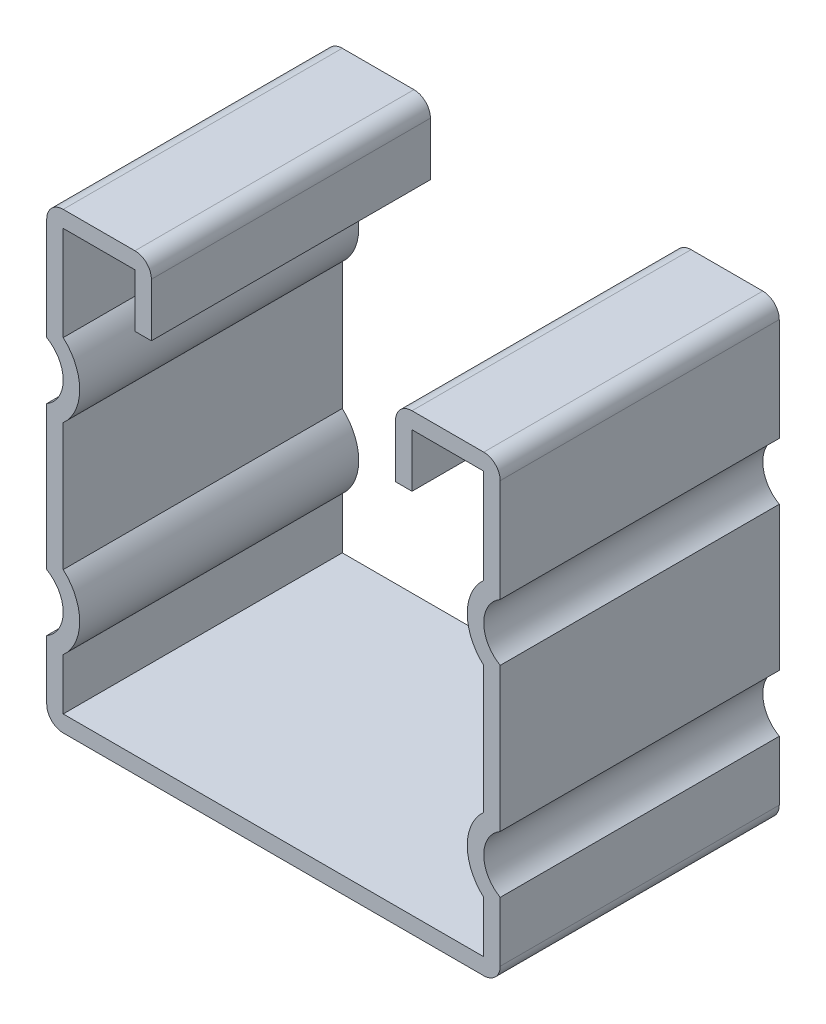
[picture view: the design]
ISO-10303-21;
HEADER;
FILE_DESCRIPTION(('STEP AP214'),'2;1');
FILE_NAME('part.step','',(''),(''),'','','');
FILE_SCHEMA(('AUTOMOTIVE_DESIGN { 1 0 10303 214 1 1 1 1 }'));
ENDSEC;
DATA;
#1=APPLICATION_CONTEXT('core data for automotive mechanical design processes');
#2=APPLICATION_PROTOCOL_DEFINITION('international standard','automotive_design',2000,#1);
#3=PRODUCT_CONTEXT('',#1,'mechanical');
#4=PRODUCT('Part','Part','',(#3));
#5=PRODUCT_RELATED_PRODUCT_CATEGORY('part','',(#4));
#6=PRODUCT_DEFINITION_FORMATION('','',#4);
#7=PRODUCT_DEFINITION_CONTEXT('part definition',#1,'design');
#8=PRODUCT_DEFINITION('design','',#6,#7);
#9=PRODUCT_DEFINITION_SHAPE('','',#8);
#10=(LENGTH_UNIT() NAMED_UNIT(*) SI_UNIT(.MILLI.,.METRE.));
#11=(NAMED_UNIT(*) PLANE_ANGLE_UNIT() SI_UNIT($,.RADIAN.));
#12=(NAMED_UNIT(*) SI_UNIT($,.STERADIAN.) SOLID_ANGLE_UNIT());
#13=UNCERTAINTY_MEASURE_WITH_UNIT(LENGTH_MEASURE(1.E-05),#10,'distance_accuracy_value','');
#14=(GEOMETRIC_REPRESENTATION_CONTEXT(3) GLOBAL_UNCERTAINTY_ASSIGNED_CONTEXT((#13)) GLOBAL_UNIT_ASSIGNED_CONTEXT((#10,
#11,#12)) REPRESENTATION_CONTEXT('',''));
#15=CARTESIAN_POINT('',(0.,0.,0.));
#16=DIRECTION('',(0.,0.,1.));
#17=DIRECTION('',(1.,0.,0.));
#18=AXIS2_PLACEMENT_3D('',#15,#16,#17);
#19=CARTESIAN_POINT('',(-19.1389,21.1074,12.7));
#20=DIRECTION('',(-1.,0.,0.));
#21=DIRECTION('',(0.,-1.,0.));
#22=AXIS2_PLACEMENT_3D('',#19,#20,#21);
#23=PLANE('',#22);
#24=DIRECTION('',(0.,1.,0.));
#25=VECTOR('',#24,1.);
#26=CARTESIAN_POINT('',(-19.1389,21.1074,-12.7));
#27=LINE('',#26,#25);
#28=CARTESIAN_POINT('',(-19.1389,12.4949714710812,-12.7));
#29=VERTEX_POINT('',#28);
#30=CARTESIAN_POINT('',(-19.1389,21.1074,-12.7));
#31=VERTEX_POINT('',#30);
#32=EDGE_CURVE('E323',#29,#31,#27,.T.);
#33=ORIENTED_EDGE('',*,*,#32,.T.);
#34=DIRECTION('',(0.,0.,-1.));
#35=VECTOR('',#34,1.);
#36=CARTESIAN_POINT('',(-19.1389,21.1074,12.7));
#37=LINE('',#36,#35);
#38=CARTESIAN_POINT('',(-19.1389,21.1074,12.7));
#39=VERTEX_POINT('',#38);
#40=EDGE_CURVE('E11',#39,#31,#37,.T.);
#41=ORIENTED_EDGE('',*,*,#40,.F.);
#42=DIRECTION('',(0.,1.,0.));
#43=VECTOR('',#42,1.);
#44=CARTESIAN_POINT('',(-19.1389,21.1074,12.7));
#45=LINE('',#44,#43);
#46=CARTESIAN_POINT('',(-19.1389,12.4949714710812,12.7));
#47=VERTEX_POINT('',#46);
#48=EDGE_CURVE('E436',#47,#39,#45,.T.);
#49=ORIENTED_EDGE('',*,*,#48,.F.);
#50=DIRECTION('',(0.,0.,-1.));
#51=VECTOR('',#50,1.);
#52=CARTESIAN_POINT('',(-19.1389,12.4949714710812,12.7));
#53=LINE('',#52,#51);
#54=EDGE_CURVE('E322',#47,#29,#53,.T.);
#55=ORIENTED_EDGE('',*,*,#54,.T.);
#56=EDGE_LOOP('',(#33,#41,#49,#55));
#57=FACE_BOUND('',#56,.T.);
#58=ADVANCED_FACE('F41',(#57),#23,.F.);
#59=CARTESIAN_POINT('',(-19.1389,21.1074,12.7));
#60=DIRECTION('',(0.,1.,0.));
#61=DIRECTION('',(-1.,0.,0.));
#62=AXIS2_PLACEMENT_3D('',#59,#60,#61);
#63=PLANE('',#62);
#64=DIRECTION('',(1.,0.,0.));
#65=VECTOR('',#64,1.);
#66=CARTESIAN_POINT('',(-19.1389,21.1074,-12.7));
#67=LINE('',#66,#65);
#68=CARTESIAN_POINT('',(-12.6111,21.1074,-12.7));
#69=VERTEX_POINT('',#68);
#70=EDGE_CURVE('E330',#31,#69,#67,.T.);
#71=ORIENTED_EDGE('',*,*,#70,.T.);
#72=DIRECTION('',(0.,0.,-1.));
#73=VECTOR('',#72,1.);
#74=CARTESIAN_POINT('',(-12.6111,21.1074,12.7));
#75=LINE('',#74,#73);
#76=CARTESIAN_POINT('',(-12.6111,21.1074,12.7));
#77=VERTEX_POINT('',#76);
#78=EDGE_CURVE('E49',#77,#69,#75,.T.);
#79=ORIENTED_EDGE('',*,*,#78,.F.);
#80=DIRECTION('',(1.,0.,0.));
#81=VECTOR('',#80,1.);
#82=CARTESIAN_POINT('',(-19.1389,21.1074,12.7));
#83=LINE('',#82,#81);
#84=EDGE_CURVE('E192',#39,#77,#83,.T.);
#85=ORIENTED_EDGE('',*,*,#84,.F.);
#86=ORIENTED_EDGE('',*,*,#40,.T.);
#87=EDGE_LOOP('',(#71,#79,#85,#86));
#88=FACE_BOUND('',#87,.T.);
#89=ADVANCED_FACE('F806',(#88),#63,.F.);
#90=CARTESIAN_POINT('',(-12.6111,21.1074,12.7));
#91=DIRECTION('',(1.,0.,0.));
#92=DIRECTION('',(0.,0.,-1.));
#93=AXIS2_PLACEMENT_3D('',#90,#91,#92);
#94=PLANE('',#93);
#95=DIRECTION('',(0.,-1.,0.));
#96=VECTOR('',#95,1.);
#97=CARTESIAN_POINT('',(-12.6111,21.1074,-12.7));
#98=LINE('',#97,#96);
#99=CARTESIAN_POINT('',(-12.6111,16.256,-12.7));
#100=VERTEX_POINT('',#99);
#101=EDGE_CURVE('E334',#69,#100,#98,.T.);
#102=ORIENTED_EDGE('',*,*,#101,.T.);
#103=DIRECTION('',(0.,0.,-1.));
#104=VECTOR('',#103,1.);
#105=CARTESIAN_POINT('',(-12.6111,16.256,12.7));
#106=LINE('',#105,#104);
#107=CARTESIAN_POINT('',(-12.6111,16.256,12.7));
#108=VERTEX_POINT('',#107);
#109=EDGE_CURVE('E566',#108,#100,#106,.T.);
#110=ORIENTED_EDGE('',*,*,#109,.F.);
#111=DIRECTION('',(0.,-1.,0.));
#112=VECTOR('',#111,1.);
#113=CARTESIAN_POINT('',(-12.6111,21.1074,12.7));
#114=LINE('',#113,#112);
#115=EDGE_CURVE('E579',#77,#108,#114,.T.);
#116=ORIENTED_EDGE('',*,*,#115,.F.);
#117=ORIENTED_EDGE('',*,*,#78,.T.);
#118=EDGE_LOOP('',(#102,#110,#116,#117));
#119=FACE_BOUND('',#118,.T.);
#120=ADVANCED_FACE('F577',(#119),#94,.F.);
#121=CARTESIAN_POINT('',(-12.6111,16.256,12.7));
#122=DIRECTION('',(0.,1.,0.));
#123=DIRECTION('',(0.,0.,1.));
#124=AXIS2_PLACEMENT_3D('',#121,#122,#123);
#125=PLANE('',#124);
#126=DIRECTION('',(1.,0.,0.));
#127=VECTOR('',#126,1.);
#128=CARTESIAN_POINT('',(-12.6111,16.256,-12.7));
#129=LINE('',#128,#127);
#130=CARTESIAN_POINT('',(-11.1125,16.256,-12.7));
#131=VERTEX_POINT('',#130);
#132=EDGE_CURVE('E333',#100,#131,#129,.T.);
#133=ORIENTED_EDGE('',*,*,#132,.T.);
#134=DIRECTION('',(0.,0.,-1.));
#135=VECTOR('',#134,1.);
#136=CARTESIAN_POINT('',(-11.1125,16.256,12.7));
#137=LINE('',#136,#135);
#138=CARTESIAN_POINT('',(-11.1125,16.256,12.7));
#139=VERTEX_POINT('',#138);
#140=EDGE_CURVE('E565',#139,#131,#137,.T.);
#141=ORIENTED_EDGE('',*,*,#140,.F.);
#142=DIRECTION('',(1.,0.,0.));
#143=VECTOR('',#142,1.);
#144=CARTESIAN_POINT('',(-12.6111,16.256,12.7));
#145=LINE('',#144,#143);
#146=EDGE_CURVE('E600',#108,#139,#145,.T.);
#147=ORIENTED_EDGE('',*,*,#146,.F.);
#148=ORIENTED_EDGE('',*,*,#109,.T.);
#149=EDGE_LOOP('',(#133,#141,#147,#148));
#150=FACE_BOUND('',#149,.T.);
#151=ADVANCED_FACE('F589',(#150),#125,.F.);
#152=CARTESIAN_POINT('',(-11.1125,21.1074,12.7));
#153=DIRECTION('',(-1.,0.,0.));
#154=DIRECTION('',(0.,-1.,0.));
#155=AXIS2_PLACEMENT_3D('',#152,#153,#154);
#156=PLANE('',#155);
#157=DIRECTION('',(0.,1.,0.));
#158=VECTOR('',#157,1.);
#159=CARTESIAN_POINT('',(-11.1125,21.1074,-12.7));
#160=LINE('',#159,#158);
#161=CARTESIAN_POINT('',(-11.1125,21.1074,-12.7));
#162=VERTEX_POINT('',#161);
#163=EDGE_CURVE('E336',#131,#162,#160,.T.);
#164=ORIENTED_EDGE('',*,*,#163,.T.);
#165=DIRECTION('',(0.,0.,-1.));
#166=VECTOR('',#165,1.);
#167=CARTESIAN_POINT('',(-11.1125,21.1074,12.7));
#168=LINE('',#167,#166);
#169=CARTESIAN_POINT('',(-11.1125,21.1074,12.7));
#170=VERTEX_POINT('',#169);
#171=EDGE_CURVE('E556',#170,#162,#168,.T.);
#172=ORIENTED_EDGE('',*,*,#171,.F.);
#173=DIRECTION('',(0.,1.,0.));
#174=VECTOR('',#173,1.);
#175=CARTESIAN_POINT('',(-11.1125,21.1074,12.7));
#176=LINE('',#175,#174);
#177=EDGE_CURVE('E595',#139,#170,#176,.T.);
#178=ORIENTED_EDGE('',*,*,#177,.F.);
#179=ORIENTED_EDGE('',*,*,#140,.T.);
#180=EDGE_LOOP('',(#164,#172,#178,#179));
#181=FACE_BOUND('',#180,.T.);
#182=ADVANCED_FACE('F592',(#181),#156,.F.);
#183=CARTESIAN_POINT('',(-12.6111,21.1074,12.7));
#184=DIRECTION('',(0.,0.,-1.));
#185=DIRECTION('',(-1.,0.,0.));
#186=AXIS2_PLACEMENT_3D('',#183,#184,#185);
#187=CYLINDRICAL_SURFACE('',#186,1.4986);
#188=CARTESIAN_POINT('',(-12.6111,21.1074,-12.7));
#189=DIRECTION('',(0.,0.,1.));
#190=DIRECTION('',(-1.,0.,0.));
#191=AXIS2_PLACEMENT_3D('',#188,#189,#190);
#192=CIRCLE('',#191,1.4986);
#193=CARTESIAN_POINT('',(-12.6111,22.606,-12.7));
#194=VERTEX_POINT('',#193);
#195=EDGE_CURVE('E342',#162,#194,#192,.T.);
#196=ORIENTED_EDGE('',*,*,#195,.T.);
#197=DIRECTION('',(0.,0.,-1.));
#198=VECTOR('',#197,1.);
#199=CARTESIAN_POINT('',(-12.6111,22.606,12.7));
#200=LINE('',#199,#198);
#201=CARTESIAN_POINT('',(-12.6111,22.606,12.7));
#202=VERTEX_POINT('',#201);
#203=EDGE_CURVE('E555',#202,#194,#200,.T.);
#204=ORIENTED_EDGE('',*,*,#203,.F.);
#205=CARTESIAN_POINT('',(-12.6111,21.1074,12.7));
#206=DIRECTION('',(0.,0.,1.));
#207=DIRECTION('',(-1.,0.,0.));
#208=AXIS2_PLACEMENT_3D('',#205,#206,#207);
#209=CIRCLE('',#208,1.4986);
#210=EDGE_CURVE('E597',#170,#202,#209,.T.);
#211=ORIENTED_EDGE('',*,*,#210,.F.);
#212=ORIENTED_EDGE('',*,*,#171,.T.);
#213=EDGE_LOOP('',(#196,#204,#211,#212));
#214=FACE_BOUND('',#213,.T.);
#215=ADVANCED_FACE('F825',(#214),#187,.T.);
#216=CARTESIAN_POINT('',(-19.1389,22.606,12.7));
#217=DIRECTION('',(0.,-1.,0.));
#218=DIRECTION('',(1.,0.,0.));
#219=AXIS2_PLACEMENT_3D('',#216,#217,#218);
#220=PLANE('',#219);
#221=DIRECTION('',(-1.,0.,0.));
#222=VECTOR('',#221,1.);
#223=CARTESIAN_POINT('',(-19.1389,22.606,-12.7));
#224=LINE('',#223,#222);
#225=CARTESIAN_POINT('',(-19.1389,22.606,-12.7));
#226=VERTEX_POINT('',#225);
#227=EDGE_CURVE('E341',#194,#226,#224,.T.);
#228=ORIENTED_EDGE('',*,*,#227,.T.);
#229=DIRECTION('',(0.,0.,-1.));
#230=VECTOR('',#229,1.);
#231=CARTESIAN_POINT('',(-19.1389,22.606,12.7));
#232=LINE('',#231,#230);
#233=CARTESIAN_POINT('',(-19.1389,22.606,12.7));
#234=VERTEX_POINT('',#233);
#235=EDGE_CURVE('E548',#234,#226,#232,.T.);
#236=ORIENTED_EDGE('',*,*,#235,.F.);
#237=DIRECTION('',(-1.,0.,0.));
#238=VECTOR('',#237,1.);
#239=CARTESIAN_POINT('',(-19.1389,22.606,12.7));
#240=LINE('',#239,#238);
#241=EDGE_CURVE('E602',#202,#234,#240,.T.);
#242=ORIENTED_EDGE('',*,*,#241,.F.);
#243=ORIENTED_EDGE('',*,*,#203,.T.);
#244=EDGE_LOOP('',(#228,#236,#242,#243));
#245=FACE_BOUND('',#244,.T.);
#246=ADVANCED_FACE('F824',(#245),#220,.F.);
#247=CARTESIAN_POINT('',(-19.1389,21.1074,12.7));
#248=DIRECTION('',(0.,0.,-1.));
#249=DIRECTION('',(-1.,0.,0.));
#250=AXIS2_PLACEMENT_3D('',#247,#248,#249);
#251=CYLINDRICAL_SURFACE('',#250,1.49860000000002);
#252=CARTESIAN_POINT('',(-19.1389,21.1074,-12.7));
#253=DIRECTION('',(0.,0.,1.));
#254=DIRECTION('',(-1.,0.,0.));
#255=AXIS2_PLACEMENT_3D('',#252,#253,#254);
#256=CIRCLE('',#255,1.49860000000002);
#257=CARTESIAN_POINT('',(-20.6375,21.1074,-12.7));
#258=VERTEX_POINT('',#257);
#259=EDGE_CURVE('E349',#226,#258,#256,.T.);
#260=ORIENTED_EDGE('',*,*,#259,.T.);
#261=DIRECTION('',(0.,0.,-1.));
#262=VECTOR('',#261,1.);
#263=CARTESIAN_POINT('',(-20.6375,21.1074,12.7));
#264=LINE('',#263,#262);
#265=CARTESIAN_POINT('',(-20.6375,21.1074,12.7));
#266=VERTEX_POINT('',#265);
#267=EDGE_CURVE('E547',#266,#258,#264,.T.);
#268=ORIENTED_EDGE('',*,*,#267,.F.);
#269=CARTESIAN_POINT('',(-19.1389,21.1074,12.7));
#270=DIRECTION('',(0.,0.,1.));
#271=DIRECTION('',(-1.,0.,0.));
#272=AXIS2_PLACEMENT_3D('',#269,#270,#271);
#273=CIRCLE('',#272,1.49860000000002);
#274=EDGE_CURVE('E610',#234,#266,#273,.T.);
#275=ORIENTED_EDGE('',*,*,#274,.F.);
#276=ORIENTED_EDGE('',*,*,#235,.T.);
#277=EDGE_LOOP('',(#260,#268,#275,#276));
#278=FACE_BOUND('',#277,.T.);
#279=ADVANCED_FACE('F827',(#278),#251,.T.);
#280=CARTESIAN_POINT('',(-20.6375,21.1074,12.7));
#281=DIRECTION('',(1.,0.,0.));
#282=DIRECTION('',(0.,0.,-1.));
#283=AXIS2_PLACEMENT_3D('',#280,#281,#282);
#284=PLANE('',#283);
#285=DIRECTION('',(0.,-1.,0.));
#286=VECTOR('',#285,1.);
#287=CARTESIAN_POINT('',(-20.6375,21.1074,-12.7));
#288=LINE('',#287,#286);
#289=CARTESIAN_POINT('',(-20.6375,11.7396513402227,-12.7));
#290=VERTEX_POINT('',#289);
#291=EDGE_CURVE('E346',#258,#290,#288,.T.);
#292=ORIENTED_EDGE('',*,*,#291,.T.);
#293=DIRECTION('',(0.,0.,-1.));
#294=VECTOR('',#293,1.);
#295=CARTESIAN_POINT('',(-20.6375,11.7396513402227,12.7));
#296=LINE('',#295,#294);
#297=CARTESIAN_POINT('',(-20.6375,11.7396513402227,12.7));
#298=VERTEX_POINT('',#297);
#299=EDGE_CURVE('E544',#298,#290,#296,.T.);
#300=ORIENTED_EDGE('',*,*,#299,.F.);
#301=DIRECTION('',(0.,-1.,0.));
#302=VECTOR('',#301,1.);
#303=CARTESIAN_POINT('',(-20.6375,21.1074,12.7));
#304=LINE('',#303,#302);
#305=EDGE_CURVE('E614',#266,#298,#304,.T.);
#306=ORIENTED_EDGE('',*,*,#305,.F.);
#307=ORIENTED_EDGE('',*,*,#267,.T.);
#308=EDGE_LOOP('',(#292,#300,#306,#307));
#309=FACE_BOUND('',#308,.T.);
#310=ADVANCED_FACE('F832',(#309),#284,.F.);
#311=CARTESIAN_POINT('',(-22.1361,9.144,12.7));
#312=DIRECTION('',(0.,0.,-1.));
#313=DIRECTION('',(-1.,0.,0.));
#314=AXIS2_PLACEMENT_3D('',#311,#312,#313);
#315=CYLINDRICAL_SURFACE('',#314,2.9972);
#316=CARTESIAN_POINT('',(-22.1361,9.144,-12.7));
#317=DIRECTION('',(0.,0.,-1.));
#318=DIRECTION('',(1.,0.,0.));
#319=AXIS2_PLACEMENT_3D('',#316,#317,#318);
#320=CIRCLE('',#319,2.9972);
#321=CARTESIAN_POINT('',(-20.6375,6.54834865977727,-12.7));
#322=VERTEX_POINT('',#321);
#323=EDGE_CURVE('E355',#290,#322,#320,.T.);
#324=ORIENTED_EDGE('',*,*,#323,.T.);
#325=DIRECTION('',(0.,0.,-1.));
#326=VECTOR('',#325,1.);
#327=CARTESIAN_POINT('',(-20.6375,6.54834865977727,12.7));
#328=LINE('',#327,#326);
#329=CARTESIAN_POINT('',(-20.6375,6.54834865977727,12.7));
#330=VERTEX_POINT('',#329);
#331=EDGE_CURVE('E539',#330,#322,#328,.T.);
#332=ORIENTED_EDGE('',*,*,#331,.F.);
#333=CARTESIAN_POINT('',(-22.1361,9.144,12.7));
#334=DIRECTION('',(0.,0.,-1.));
#335=DIRECTION('',(1.,0.,0.));
#336=AXIS2_PLACEMENT_3D('',#333,#334,#335);
#337=CIRCLE('',#336,2.9972);
#338=EDGE_CURVE('E613',#298,#330,#337,.T.);
#339=ORIENTED_EDGE('',*,*,#338,.F.);
#340=ORIENTED_EDGE('',*,*,#299,.T.);
#341=EDGE_LOOP('',(#324,#332,#339,#340));
#342=FACE_BOUND('',#341,.T.);
#343=ADVANCED_FACE('F840',(#342),#315,.F.);
#344=CARTESIAN_POINT('',(-20.6375,6.54834865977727,12.7));
#345=DIRECTION('',(1.,0.,0.));
#346=DIRECTION('',(0.,0.,-1.));
#347=AXIS2_PLACEMENT_3D('',#344,#345,#346);
#348=PLANE('',#347);
#349=DIRECTION('',(0.,-1.,0.));
#350=VECTOR('',#349,1.);
#351=CARTESIAN_POINT('',(-20.6375,6.54834865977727,-12.7));
#352=LINE('',#351,#350);
#353=CARTESIAN_POINT('',(-20.6375,-6.54834865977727,-12.7));
#354=VERTEX_POINT('',#353);
#355=EDGE_CURVE('E358',#322,#354,#352,.T.);
#356=ORIENTED_EDGE('',*,*,#355,.T.);
#357=DIRECTION('',(0.,0.,-1.));
#358=VECTOR('',#357,1.);
#359=CARTESIAN_POINT('',(-20.6375,-6.54834865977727,12.7));
#360=LINE('',#359,#358);
#361=CARTESIAN_POINT('',(-20.6375,-6.54834865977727,12.7));
#362=VERTEX_POINT('',#361);
#363=EDGE_CURVE('E534',#362,#354,#360,.T.);
#364=ORIENTED_EDGE('',*,*,#363,.F.);
#365=DIRECTION('',(0.,-1.,0.));
#366=VECTOR('',#365,1.);
#367=CARTESIAN_POINT('',(-20.6375,6.54834865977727,12.7));
#368=LINE('',#367,#366);
#369=EDGE_CURVE('E616',#330,#362,#368,.T.);
#370=ORIENTED_EDGE('',*,*,#369,.F.);
#371=ORIENTED_EDGE('',*,*,#331,.T.);
#372=EDGE_LOOP('',(#356,#364,#370,#371));
#373=FACE_BOUND('',#372,.T.);
#374=ADVANCED_FACE('F842',(#373),#348,.F.);
#375=CARTESIAN_POINT('',(-22.1361,-9.144,12.7));
#376=DIRECTION('',(0.,0.,-1.));
#377=DIRECTION('',(-1.,0.,0.));
#378=AXIS2_PLACEMENT_3D('',#375,#376,#377);
#379=CYLINDRICAL_SURFACE('',#378,2.9972);
#380=CARTESIAN_POINT('',(-22.1361,-9.144,-12.7));
#381=DIRECTION('',(0.,0.,-1.));
#382=DIRECTION('',(-1.,0.,0.));
#383=AXIS2_PLACEMENT_3D('',#380,#381,#382);
#384=CIRCLE('',#383,2.9972);
#385=CARTESIAN_POINT('',(-20.6375,-11.7396513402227,-12.7));
#386=VERTEX_POINT('',#385);
#387=EDGE_CURVE('E360',#354,#386,#384,.T.);
#388=ORIENTED_EDGE('',*,*,#387,.T.);
#389=DIRECTION('',(0.,0.,-1.));
#390=VECTOR('',#389,1.);
#391=CARTESIAN_POINT('',(-20.6375,-11.7396513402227,12.7));
#392=LINE('',#391,#390);
#393=CARTESIAN_POINT('',(-20.6375,-11.7396513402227,12.7));
#394=VERTEX_POINT('',#393);
#395=EDGE_CURVE('E528',#394,#386,#392,.T.);
#396=ORIENTED_EDGE('',*,*,#395,.F.);
#397=CARTESIAN_POINT('',(-22.1361,-9.144,12.7));
#398=DIRECTION('',(0.,0.,-1.));
#399=DIRECTION('',(-1.,0.,0.));
#400=AXIS2_PLACEMENT_3D('',#397,#398,#399);
#401=CIRCLE('',#400,2.9972);
#402=EDGE_CURVE('E623',#362,#394,#401,.T.);
#403=ORIENTED_EDGE('',*,*,#402,.F.);
#404=ORIENTED_EDGE('',*,*,#363,.T.);
#405=EDGE_LOOP('',(#388,#396,#403,#404));
#406=FACE_BOUND('',#405,.T.);
#407=ADVANCED_FACE('F843',(#406),#379,.F.);
#408=CARTESIAN_POINT('',(-20.6375,-11.7396513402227,12.7));
#409=DIRECTION('',(1.,0.,0.));
#410=DIRECTION('',(0.,1.,0.));
#411=AXIS2_PLACEMENT_3D('',#408,#409,#410);
#412=PLANE('',#411);
#413=DIRECTION('',(0.,-1.,0.));
#414=VECTOR('',#413,1.);
#415=CARTESIAN_POINT('',(-20.6375,-11.7396513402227,-12.7));
#416=LINE('',#415,#414);
#417=CARTESIAN_POINT('',(-20.6375,-17.1704,-12.7));
#418=VERTEX_POINT('',#417);
#419=EDGE_CURVE('E365',#386,#418,#416,.T.);
#420=ORIENTED_EDGE('',*,*,#419,.T.);
#421=DIRECTION('',(0.,0.,-1.));
#422=VECTOR('',#421,1.);
#423=CARTESIAN_POINT('',(-20.6375,-17.1704,12.7));
#424=LINE('',#423,#422);
#425=CARTESIAN_POINT('',(-20.6375,-17.1704,12.7));
#426=VERTEX_POINT('',#425);
#427=EDGE_CURVE('E527',#426,#418,#424,.T.);
#428=ORIENTED_EDGE('',*,*,#427,.F.);
#429=DIRECTION('',(0.,-1.,0.));
#430=VECTOR('',#429,1.);
#431=CARTESIAN_POINT('',(-20.6375,-11.7396513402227,12.7));
#432=LINE('',#431,#430);
#433=EDGE_CURVE('E624',#394,#426,#432,.T.);
#434=ORIENTED_EDGE('',*,*,#433,.F.);
#435=ORIENTED_EDGE('',*,*,#395,.T.);
#436=EDGE_LOOP('',(#420,#428,#434,#435));
#437=FACE_BOUND('',#436,.T.);
#438=ADVANCED_FACE('F850',(#437),#412,.F.);
#439=CARTESIAN_POINT('',(-19.1389,-17.1704,12.7));
#440=DIRECTION('',(0.,0.,-1.));
#441=DIRECTION('',(-1.,0.,0.));
#442=AXIS2_PLACEMENT_3D('',#439,#440,#441);
#443=CYLINDRICAL_SURFACE('',#442,1.4986);
#444=CARTESIAN_POINT('',(-19.1389,-17.1704,-12.7));
#445=DIRECTION('',(0.,0.,1.));
#446=DIRECTION('',(-1.,0.,0.));
#447=AXIS2_PLACEMENT_3D('',#444,#445,#446);
#448=CIRCLE('',#447,1.4986);
#449=CARTESIAN_POINT('',(-19.1389,-18.669,-12.7));
#450=VERTEX_POINT('',#449);
#451=EDGE_CURVE('E362',#418,#450,#448,.T.);
#452=ORIENTED_EDGE('',*,*,#451,.T.);
#453=DIRECTION('',(0.,0.,-1.));
#454=VECTOR('',#453,1.);
#455=CARTESIAN_POINT('',(-19.1389,-18.669,12.7));
#456=LINE('',#455,#454);
#457=CARTESIAN_POINT('',(-19.1389,-18.669,12.7));
#458=VERTEX_POINT('',#457);
#459=EDGE_CURVE('E524',#458,#450,#456,.T.);
#460=ORIENTED_EDGE('',*,*,#459,.F.);
#461=CARTESIAN_POINT('',(-19.1389,-17.1704,12.7));
#462=DIRECTION('',(0.,0.,1.));
#463=DIRECTION('',(-1.,0.,0.));
#464=AXIS2_PLACEMENT_3D('',#461,#462,#463);
#465=CIRCLE('',#464,1.4986);
#466=EDGE_CURVE('E630',#426,#458,#465,.T.);
#467=ORIENTED_EDGE('',*,*,#466,.F.);
#468=ORIENTED_EDGE('',*,*,#427,.T.);
#469=EDGE_LOOP('',(#452,#460,#467,#468));
#470=FACE_BOUND('',#469,.T.);
#471=ADVANCED_FACE('F855',(#470),#443,.T.);
#472=CARTESIAN_POINT('',(-19.1389,-18.669,12.7));
#473=DIRECTION('',(0.,1.,0.));
#474=DIRECTION('',(0.,0.,1.));
#475=AXIS2_PLACEMENT_3D('',#472,#473,#474);
#476=PLANE('',#475);
#477=DIRECTION('',(1.,0.,0.));
#478=VECTOR('',#477,1.);
#479=CARTESIAN_POINT('',(-19.1389,-18.669,-12.7));
#480=LINE('',#479,#478);
#481=CARTESIAN_POINT('',(19.1389,-18.669,-12.7));
#482=VERTEX_POINT('',#481);
#483=EDGE_CURVE('E368',#450,#482,#480,.T.);
#484=ORIENTED_EDGE('',*,*,#483,.T.);
#485=DIRECTION('',(0.,0.,-1.));
#486=VECTOR('',#485,1.);
#487=CARTESIAN_POINT('',(19.1389,-18.669,12.7));
#488=LINE('',#487,#486);
#489=CARTESIAN_POINT('',(19.1389,-18.669,12.7));
#490=VERTEX_POINT('',#489);
#491=EDGE_CURVE('E519',#490,#482,#488,.T.);
#492=ORIENTED_EDGE('',*,*,#491,.F.);
#493=DIRECTION('',(1.,0.,0.));
#494=VECTOR('',#493,1.);
#495=CARTESIAN_POINT('',(-19.1389,-18.669,12.7));
#496=LINE('',#495,#494);
#497=EDGE_CURVE('E629',#458,#490,#496,.T.);
#498=ORIENTED_EDGE('',*,*,#497,.F.);
#499=ORIENTED_EDGE('',*,*,#459,.T.);
#500=EDGE_LOOP('',(#484,#492,#498,#499));
#501=FACE_BOUND('',#500,.T.);
#502=ADVANCED_FACE('F860',(#501),#476,.F.);
#503=CARTESIAN_POINT('',(19.1389,-17.1704,12.7));
#504=DIRECTION('',(0.,0.,-1.));
#505=DIRECTION('',(-1.,0.,0.));
#506=AXIS2_PLACEMENT_3D('',#503,#504,#505);
#507=CYLINDRICAL_SURFACE('',#506,1.4986);
#508=CARTESIAN_POINT('',(19.1389,-17.1704,-12.7));
#509=DIRECTION('',(0.,0.,1.));
#510=DIRECTION('',(-1.,0.,0.));
#511=AXIS2_PLACEMENT_3D('',#508,#509,#510);
#512=CIRCLE('',#511,1.4986);
#513=CARTESIAN_POINT('',(20.6375,-17.1704,-12.7));
#514=VERTEX_POINT('',#513);
#515=EDGE_CURVE('E371',#482,#514,#512,.T.);
#516=ORIENTED_EDGE('',*,*,#515,.T.);
#517=DIRECTION('',(0.,0.,-1.));
#518=VECTOR('',#517,1.);
#519=CARTESIAN_POINT('',(20.6375,-17.1704,12.7));
#520=LINE('',#519,#518);
#521=CARTESIAN_POINT('',(20.6375,-17.1704,12.7));
#522=VERTEX_POINT('',#521);
#523=EDGE_CURVE('E511',#522,#514,#520,.T.);
#524=ORIENTED_EDGE('',*,*,#523,.F.);
#525=CARTESIAN_POINT('',(19.1389,-17.1704,12.7));
#526=DIRECTION('',(0.,0.,1.));
#527=DIRECTION('',(-1.,0.,0.));
#528=AXIS2_PLACEMENT_3D('',#525,#526,#527);
#529=CIRCLE('',#528,1.4986);
#530=EDGE_CURVE('E633',#490,#522,#529,.T.);
#531=ORIENTED_EDGE('',*,*,#530,.F.);
#532=ORIENTED_EDGE('',*,*,#491,.T.);
#533=EDGE_LOOP('',(#516,#524,#531,#532));
#534=FACE_BOUND('',#533,.T.);
#535=ADVANCED_FACE('F862',(#534),#507,.T.);
#536=CARTESIAN_POINT('',(20.6375,-17.1704,12.7));
#537=DIRECTION('',(-1.,0.,0.));
#538=DIRECTION('',(0.,-1.,0.));
#539=AXIS2_PLACEMENT_3D('',#536,#537,#538);
#540=PLANE('',#539);
#541=DIRECTION('',(0.,1.,0.));
#542=VECTOR('',#541,1.);
#543=CARTESIAN_POINT('',(20.6375,-17.1704,-12.7));
#544=LINE('',#543,#542);
#545=CARTESIAN_POINT('',(20.6375,-11.7396513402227,-12.7));
#546=VERTEX_POINT('',#545);
#547=EDGE_CURVE('E372',#514,#546,#544,.T.);
#548=ORIENTED_EDGE('',*,*,#547,.T.);
#549=DIRECTION('',(0.,0.,-1.));
#550=VECTOR('',#549,1.);
#551=CARTESIAN_POINT('',(20.6375,-11.7396513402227,12.7));
#552=LINE('',#551,#550);
#553=CARTESIAN_POINT('',(20.6375,-11.7396513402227,12.7));
#554=VERTEX_POINT('',#553);
#555=EDGE_CURVE('E509',#554,#546,#552,.T.);
#556=ORIENTED_EDGE('',*,*,#555,.F.);
#557=DIRECTION('',(0.,1.,0.));
#558=VECTOR('',#557,1.);
#559=CARTESIAN_POINT('',(20.6375,-17.1704,12.7));
#560=LINE('',#559,#558);
#561=EDGE_CURVE('E636',#522,#554,#560,.T.);
#562=ORIENTED_EDGE('',*,*,#561,.F.);
#563=ORIENTED_EDGE('',*,*,#523,.T.);
#564=EDGE_LOOP('',(#548,#556,#562,#563));
#565=FACE_BOUND('',#564,.T.);
#566=ADVANCED_FACE('F863',(#565),#540,.F.);
#567=CARTESIAN_POINT('',(22.1361,-9.144,12.7));
#568=DIRECTION('',(0.,0.,-1.));
#569=DIRECTION('',(-1.,0.,0.));
#570=AXIS2_PLACEMENT_3D('',#567,#568,#569);
#571=CYLINDRICAL_SURFACE('',#570,2.9972);
#572=CARTESIAN_POINT('',(22.1361,-9.144,-12.7));
#573=DIRECTION('',(0.,0.,-1.));
#574=DIRECTION('',(-1.,0.,0.));
#575=AXIS2_PLACEMENT_3D('',#572,#573,#574);
#576=CIRCLE('',#575,2.9972);
#577=CARTESIAN_POINT('',(20.6375,-6.54834865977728,-12.7));
#578=VERTEX_POINT('',#577);
#579=EDGE_CURVE('E380',#546,#578,#576,.T.);
#580=ORIENTED_EDGE('',*,*,#579,.T.);
#581=DIRECTION('',(0.,0.,-1.));
#582=VECTOR('',#581,1.);
#583=CARTESIAN_POINT('',(20.6375,-6.54834865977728,12.7));
#584=LINE('',#583,#582);
#585=CARTESIAN_POINT('',(20.6375,-6.54834865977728,12.7));
#586=VERTEX_POINT('',#585);
#587=EDGE_CURVE('E506',#586,#578,#584,.T.);
#588=ORIENTED_EDGE('',*,*,#587,.F.);
#589=CARTESIAN_POINT('',(22.1361,-9.144,12.7));
#590=DIRECTION('',(0.,0.,-1.));
#591=DIRECTION('',(-1.,0.,0.));
#592=AXIS2_PLACEMENT_3D('',#589,#590,#591);
#593=CIRCLE('',#592,2.9972);
#594=EDGE_CURVE('E638',#554,#586,#593,.T.);
#595=ORIENTED_EDGE('',*,*,#594,.F.);
#596=ORIENTED_EDGE('',*,*,#555,.T.);
#597=EDGE_LOOP('',(#580,#588,#595,#596));
#598=FACE_BOUND('',#597,.T.);
#599=ADVANCED_FACE('F870',(#598),#571,.F.);
#600=CARTESIAN_POINT('',(20.6375,-6.54834865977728,12.7));
#601=DIRECTION('',(-1.,0.,0.));
#602=DIRECTION('',(0.,0.,1.));
#603=AXIS2_PLACEMENT_3D('',#600,#601,#602);
#604=PLANE('',#603);
#605=DIRECTION('',(0.,1.,0.));
#606=VECTOR('',#605,1.);
#607=CARTESIAN_POINT('',(20.6375,-6.54834865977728,-12.7));
#608=LINE('',#607,#606);
#609=CARTESIAN_POINT('',(20.6375,6.54834865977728,-12.7));
#610=VERTEX_POINT('',#609);
#611=EDGE_CURVE('E379',#578,#610,#608,.T.);
#612=ORIENTED_EDGE('',*,*,#611,.T.);
#613=DIRECTION('',(0.,0.,-1.));
#614=VECTOR('',#613,1.);
#615=CARTESIAN_POINT('',(20.6375,6.54834865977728,12.7));
#616=LINE('',#615,#614);
#617=CARTESIAN_POINT('',(20.6375,6.54834865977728,12.7));
#618=VERTEX_POINT('',#617);
#619=EDGE_CURVE('E505',#618,#610,#616,.T.);
#620=ORIENTED_EDGE('',*,*,#619,.F.);
#621=DIRECTION('',(0.,1.,0.));
#622=VECTOR('',#621,1.);
#623=CARTESIAN_POINT('',(20.6375,-6.54834865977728,12.7));
#624=LINE('',#623,#622);
#625=EDGE_CURVE('E645',#586,#618,#624,.T.);
#626=ORIENTED_EDGE('',*,*,#625,.F.);
#627=ORIENTED_EDGE('',*,*,#587,.T.);
#628=EDGE_LOOP('',(#612,#620,#626,#627));
#629=FACE_BOUND('',#628,.T.);
#630=ADVANCED_FACE('F875',(#629),#604,.F.);
#631=CARTESIAN_POINT('',(22.1361,9.144,12.7));
#632=DIRECTION('',(0.,0.,-1.));
#633=DIRECTION('',(-1.,0.,0.));
#634=AXIS2_PLACEMENT_3D('',#631,#632,#633);
#635=CYLINDRICAL_SURFACE('',#634,2.9972);
#636=CARTESIAN_POINT('',(22.1361,9.144,-12.7));
#637=DIRECTION('',(0.,0.,-1.));
#638=DIRECTION('',(1.,0.,0.));
#639=AXIS2_PLACEMENT_3D('',#636,#637,#638);
#640=CIRCLE('',#639,2.9972);
#641=CARTESIAN_POINT('',(20.6375,11.7396513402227,-12.7));
#642=VERTEX_POINT('',#641);
#643=EDGE_CURVE('E384',#610,#642,#640,.T.);
#644=ORIENTED_EDGE('',*,*,#643,.T.);
#645=DIRECTION('',(0.,0.,-1.));
#646=VECTOR('',#645,1.);
#647=CARTESIAN_POINT('',(20.6375,11.7396513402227,12.7));
#648=LINE('',#647,#646);
#649=CARTESIAN_POINT('',(20.6375,11.7396513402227,12.7));
#650=VERTEX_POINT('',#649);
#651=EDGE_CURVE('E498',#650,#642,#648,.T.);
#652=ORIENTED_EDGE('',*,*,#651,.F.);
#653=CARTESIAN_POINT('',(22.1361,9.144,12.7));
#654=DIRECTION('',(0.,0.,-1.));
#655=DIRECTION('',(1.,0.,0.));
#656=AXIS2_PLACEMENT_3D('',#653,#654,#655);
#657=CIRCLE('',#656,2.9972);
#658=EDGE_CURVE('E643',#618,#650,#657,.T.);
#659=ORIENTED_EDGE('',*,*,#658,.F.);
#660=ORIENTED_EDGE('',*,*,#619,.T.);
#661=EDGE_LOOP('',(#644,#652,#659,#660));
#662=FACE_BOUND('',#661,.T.);
#663=ADVANCED_FACE('F877',(#662),#635,.F.);
#664=CARTESIAN_POINT('',(20.6375,11.7396513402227,12.7));
#665=DIRECTION('',(-1.,0.,0.));
#666=DIRECTION('',(0.,-1.,0.));
#667=AXIS2_PLACEMENT_3D('',#664,#665,#666);
#668=PLANE('',#667);
#669=DIRECTION('',(0.,1.,0.));
#670=VECTOR('',#669,1.);
#671=CARTESIAN_POINT('',(20.6375,11.7396513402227,-12.7));
#672=LINE('',#671,#670);
#673=CARTESIAN_POINT('',(20.6375,21.1074,-12.7));
#674=VERTEX_POINT('',#673);
#675=EDGE_CURVE('E387',#642,#674,#672,.T.);
#676=ORIENTED_EDGE('',*,*,#675,.T.);
#677=DIRECTION('',(0.,0.,-1.));
#678=VECTOR('',#677,1.);
#679=CARTESIAN_POINT('',(20.6375,21.1074,12.7));
#680=LINE('',#679,#678);
#681=CARTESIAN_POINT('',(20.6375,21.1074,12.7));
#682=VERTEX_POINT('',#681);
#683=EDGE_CURVE('E494',#682,#674,#680,.T.);
#684=ORIENTED_EDGE('',*,*,#683,.F.);
#685=DIRECTION('',(0.,1.,0.));
#686=VECTOR('',#685,1.);
#687=CARTESIAN_POINT('',(20.6375,11.7396513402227,12.7));
#688=LINE('',#687,#686);
#689=EDGE_CURVE('E649',#650,#682,#688,.T.);
#690=ORIENTED_EDGE('',*,*,#689,.F.);
#691=ORIENTED_EDGE('',*,*,#651,.T.);
#692=EDGE_LOOP('',(#676,#684,#690,#691));
#693=FACE_BOUND('',#692,.T.);
#694=ADVANCED_FACE('F883',(#693),#668,.F.);
#695=CARTESIAN_POINT('',(19.1389,21.1074,12.7));
#696=DIRECTION('',(0.,0.,-1.));
#697=DIRECTION('',(-1.,0.,0.));
#698=AXIS2_PLACEMENT_3D('',#695,#696,#697);
#699=CYLINDRICAL_SURFACE('',#698,1.4986);
#700=CARTESIAN_POINT('',(19.1389,21.1074,-12.7));
#701=DIRECTION('',(0.,0.,1.));
#702=DIRECTION('',(-1.,0.,0.));
#703=AXIS2_PLACEMENT_3D('',#700,#701,#702);
#704=CIRCLE('',#703,1.4986);
#705=CARTESIAN_POINT('',(19.1389,22.606,-12.7));
#706=VERTEX_POINT('',#705);
#707=EDGE_CURVE('E386',#674,#706,#704,.T.);
#708=ORIENTED_EDGE('',*,*,#707,.T.);
#709=DIRECTION('',(0.,0.,-1.));
#710=VECTOR('',#709,1.);
#711=CARTESIAN_POINT('',(19.1389,22.606,12.7));
#712=LINE('',#711,#710);
#713=CARTESIAN_POINT('',(19.1389,22.606,12.7));
#714=VERTEX_POINT('',#713);
#715=EDGE_CURVE('E489',#714,#706,#712,.T.);
#716=ORIENTED_EDGE('',*,*,#715,.F.);
#717=CARTESIAN_POINT('',(19.1389,21.1074,12.7));
#718=DIRECTION('',(0.,0.,1.));
#719=DIRECTION('',(-1.,0.,0.));
#720=AXIS2_PLACEMENT_3D('',#717,#718,#719);
#721=CIRCLE('',#720,1.4986);
#722=EDGE_CURVE('E653',#682,#714,#721,.T.);
#723=ORIENTED_EDGE('',*,*,#722,.F.);
#724=ORIENTED_EDGE('',*,*,#683,.T.);
#725=EDGE_LOOP('',(#708,#716,#723,#724));
#726=FACE_BOUND('',#725,.T.);
#727=ADVANCED_FACE('F882',(#726),#699,.T.);
#728=CARTESIAN_POINT('',(19.1389,22.606,12.7));
#729=DIRECTION('',(0.,-1.,0.));
#730=DIRECTION('',(0.,0.,-1.));
#731=AXIS2_PLACEMENT_3D('',#728,#729,#730);
#732=PLANE('',#731);
#733=DIRECTION('',(-1.,0.,0.));
#734=VECTOR('',#733,1.);
#735=CARTESIAN_POINT('',(19.1389,22.606,-12.7));
#736=LINE('',#735,#734);
#737=CARTESIAN_POINT('',(12.6111,22.606,-12.7));
#738=VERTEX_POINT('',#737);
#739=EDGE_CURVE('E394',#706,#738,#736,.T.);
#740=ORIENTED_EDGE('',*,*,#739,.T.);
#741=DIRECTION('',(0.,0.,-1.));
#742=VECTOR('',#741,1.);
#743=CARTESIAN_POINT('',(12.6111,22.606,12.7));
#744=LINE('',#743,#742);
#745=CARTESIAN_POINT('',(12.6111,22.606,12.7));
#746=VERTEX_POINT('',#745);
#747=EDGE_CURVE('E488',#746,#738,#744,.T.);
#748=ORIENTED_EDGE('',*,*,#747,.F.);
#749=DIRECTION('',(-1.,0.,0.));
#750=VECTOR('',#749,1.);
#751=CARTESIAN_POINT('',(19.1389,22.606,12.7));
#752=LINE('',#751,#750);
#753=EDGE_CURVE('E655',#714,#746,#752,.T.);
#754=ORIENTED_EDGE('',*,*,#753,.F.);
#755=ORIENTED_EDGE('',*,*,#715,.T.);
#756=EDGE_LOOP('',(#740,#748,#754,#755));
#757=FACE_BOUND('',#756,.T.);
#758=ADVANCED_FACE('F887',(#757),#732,.F.);
#759=CARTESIAN_POINT('',(12.6111,21.1074,12.7));
#760=DIRECTION('',(0.,0.,-1.));
#761=DIRECTION('',(-1.,0.,0.));
#762=AXIS2_PLACEMENT_3D('',#759,#760,#761);
#763=CYLINDRICAL_SURFACE('',#762,1.4986);
#764=CARTESIAN_POINT('',(12.6111,21.1074,-12.7));
#765=DIRECTION('',(0.,0.,1.));
#766=DIRECTION('',(-1.,0.,0.));
#767=AXIS2_PLACEMENT_3D('',#764,#765,#766);
#768=CIRCLE('',#767,1.4986);
#769=CARTESIAN_POINT('',(11.1125,21.1074,-12.7));
#770=VERTEX_POINT('',#769);
#771=EDGE_CURVE('E391',#738,#770,#768,.T.);
#772=ORIENTED_EDGE('',*,*,#771,.T.);
#773=DIRECTION('',(0.,0.,-1.));
#774=VECTOR('',#773,1.);
#775=CARTESIAN_POINT('',(11.1125,21.1074,12.7));
#776=LINE('',#775,#774);
#777=CARTESIAN_POINT('',(11.1125,21.1074,12.7));
#778=VERTEX_POINT('',#777);
#779=EDGE_CURVE('E484',#778,#770,#776,.T.);
#780=ORIENTED_EDGE('',*,*,#779,.F.);
#781=CARTESIAN_POINT('',(12.6111,21.1074,12.7));
#782=DIRECTION('',(0.,0.,1.));
#783=DIRECTION('',(-1.,0.,0.));
#784=AXIS2_PLACEMENT_3D('',#781,#782,#783);
#785=CIRCLE('',#784,1.4986);
#786=EDGE_CURVE('E659',#746,#778,#785,.T.);
#787=ORIENTED_EDGE('',*,*,#786,.F.);
#788=ORIENTED_EDGE('',*,*,#747,.T.);
#789=EDGE_LOOP('',(#772,#780,#787,#788));
#790=FACE_BOUND('',#789,.T.);
#791=ADVANCED_FACE('F893',(#790),#763,.T.);
#792=CARTESIAN_POINT('',(11.1125,21.1074,12.7));
#793=DIRECTION('',(1.,0.,0.));
#794=DIRECTION('',(0.,0.,-1.));
#795=AXIS2_PLACEMENT_3D('',#792,#793,#794);
#796=PLANE('',#795);
#797=DIRECTION('',(0.,-1.,0.));
#798=VECTOR('',#797,1.);
#799=CARTESIAN_POINT('',(11.1125,21.1074,-12.7));
#800=LINE('',#799,#798);
#801=CARTESIAN_POINT('',(11.1125,16.256,-12.7));
#802=VERTEX_POINT('',#801);
#803=EDGE_CURVE('E400',#770,#802,#800,.T.);
#804=ORIENTED_EDGE('',*,*,#803,.T.);
#805=DIRECTION('',(0.,0.,-1.));
#806=VECTOR('',#805,1.);
#807=CARTESIAN_POINT('',(11.1125,16.256,12.7));
#808=LINE('',#807,#806);
#809=CARTESIAN_POINT('',(11.1125,16.256,12.7));
#810=VERTEX_POINT('',#809);
#811=EDGE_CURVE('E477',#810,#802,#808,.T.);
#812=ORIENTED_EDGE('',*,*,#811,.F.);
#813=DIRECTION('',(0.,-1.,0.));
#814=VECTOR('',#813,1.);
#815=CARTESIAN_POINT('',(11.1125,21.1074,12.7));
#816=LINE('',#815,#814);
#817=EDGE_CURVE('E658',#778,#810,#816,.T.);
#818=ORIENTED_EDGE('',*,*,#817,.F.);
#819=ORIENTED_EDGE('',*,*,#779,.T.);
#820=EDGE_LOOP('',(#804,#812,#818,#819));
#821=FACE_BOUND('',#820,.T.);
#822=ADVANCED_FACE('F900',(#821),#796,.F.);
#823=CARTESIAN_POINT('',(11.1125,16.256,12.7));
#824=DIRECTION('',(0.,1.,0.));
#825=DIRECTION('',(-1.,0.,0.));
#826=AXIS2_PLACEMENT_3D('',#823,#824,#825);
#827=PLANE('',#826);
#828=DIRECTION('',(1.,0.,0.));
#829=VECTOR('',#828,1.);
#830=CARTESIAN_POINT('',(11.1125,16.256,-12.7));
#831=LINE('',#830,#829);
#832=CARTESIAN_POINT('',(12.6111,16.256,-12.7));
#833=VERTEX_POINT('',#832);
#834=EDGE_CURVE('E402',#802,#833,#831,.T.);
#835=ORIENTED_EDGE('',*,*,#834,.T.);
#836=DIRECTION('',(0.,0.,-1.));
#837=VECTOR('',#836,1.);
#838=CARTESIAN_POINT('',(12.6111,16.256,12.7));
#839=LINE('',#838,#837);
#840=CARTESIAN_POINT('',(12.6111,16.256,12.7));
#841=VERTEX_POINT('',#840);
#842=EDGE_CURVE('E471',#841,#833,#839,.T.);
#843=ORIENTED_EDGE('',*,*,#842,.F.);
#844=DIRECTION('',(1.,0.,0.));
#845=VECTOR('',#844,1.);
#846=CARTESIAN_POINT('',(11.1125,16.256,12.7));
#847=LINE('',#846,#845);
#848=EDGE_CURVE('E661',#810,#841,#847,.T.);
#849=ORIENTED_EDGE('',*,*,#848,.F.);
#850=ORIENTED_EDGE('',*,*,#811,.T.);
#851=EDGE_LOOP('',(#835,#843,#849,#850));
#852=FACE_BOUND('',#851,.T.);
#853=ADVANCED_FACE('F902',(#852),#827,.F.);
#854=CARTESIAN_POINT('',(12.6111,21.1074,12.7));
#855=DIRECTION('',(-1.,0.,0.));
#856=DIRECTION('',(0.,0.,1.));
#857=AXIS2_PLACEMENT_3D('',#854,#855,#856);
#858=PLANE('',#857);
#859=DIRECTION('',(0.,1.,0.));
#860=VECTOR('',#859,1.);
#861=CARTESIAN_POINT('',(12.6111,21.1074,-12.7));
#862=LINE('',#861,#860);
#863=CARTESIAN_POINT('',(12.6111,21.1074,-12.7));
#864=VERTEX_POINT('',#863);
#865=EDGE_CURVE('E404',#833,#864,#862,.T.);
#866=ORIENTED_EDGE('',*,*,#865,.T.);
#867=DIRECTION('',(0.,0.,-1.));
#868=VECTOR('',#867,1.);
#869=CARTESIAN_POINT('',(12.6111,21.1074,12.7));
#870=LINE('',#869,#868);
#871=CARTESIAN_POINT('',(12.6111,21.1074,12.7));
#872=VERTEX_POINT('',#871);
#873=EDGE_CURVE('E468',#872,#864,#870,.T.);
#874=ORIENTED_EDGE('',*,*,#873,.F.);
#875=DIRECTION('',(0.,1.,0.));
#876=VECTOR('',#875,1.);
#877=CARTESIAN_POINT('',(12.6111,21.1074,12.7));
#878=LINE('',#877,#876);
#879=EDGE_CURVE('E667',#841,#872,#878,.T.);
#880=ORIENTED_EDGE('',*,*,#879,.F.);
#881=ORIENTED_EDGE('',*,*,#842,.T.);
#882=EDGE_LOOP('',(#866,#874,#880,#881));
#883=FACE_BOUND('',#882,.T.);
#884=ADVANCED_FACE('F903',(#883),#858,.F.);
#885=CARTESIAN_POINT('',(19.1389,21.1074,12.7));
#886=DIRECTION('',(0.,1.,0.));
#887=DIRECTION('',(0.,0.,1.));
#888=AXIS2_PLACEMENT_3D('',#885,#886,#887);
#889=PLANE('',#888);
#890=DIRECTION('',(1.,0.,0.));
#891=VECTOR('',#890,1.);
#892=CARTESIAN_POINT('',(19.1389,21.1074,-12.7));
#893=LINE('',#892,#891);
#894=CARTESIAN_POINT('',(19.1389,21.1074,-12.7));
#895=VERTEX_POINT('',#894);
#896=EDGE_CURVE('E410',#864,#895,#893,.T.);
#897=ORIENTED_EDGE('',*,*,#896,.T.);
#898=DIRECTION('',(0.,0.,-1.));
#899=VECTOR('',#898,1.);
#900=CARTESIAN_POINT('',(19.1389,21.1074,12.7));
#901=LINE('',#900,#899);
#902=CARTESIAN_POINT('',(19.1389,21.1074,12.7));
#903=VERTEX_POINT('',#902);
#904=EDGE_CURVE('E467',#903,#895,#901,.T.);
#905=ORIENTED_EDGE('',*,*,#904,.F.);
#906=DIRECTION('',(1.,0.,0.));
#907=VECTOR('',#906,1.);
#908=CARTESIAN_POINT('',(19.1389,21.1074,12.7));
#909=LINE('',#908,#907);
#910=EDGE_CURVE('E666',#872,#903,#909,.T.);
#911=ORIENTED_EDGE('',*,*,#910,.F.);
#912=ORIENTED_EDGE('',*,*,#873,.T.);
#913=EDGE_LOOP('',(#897,#905,#911,#912));
#914=FACE_BOUND('',#913,.T.);
#915=ADVANCED_FACE('F906',(#914),#889,.F.);
#916=CARTESIAN_POINT('',(19.1389,12.4949714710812,12.7));
#917=DIRECTION('',(1.,0.,0.));
#918=DIRECTION('',(0.,1.,0.));
#919=AXIS2_PLACEMENT_3D('',#916,#917,#918);
#920=PLANE('',#919);
#921=DIRECTION('',(0.,-1.,0.));
#922=VECTOR('',#921,1.);
#923=CARTESIAN_POINT('',(19.1389,12.4949714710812,-12.7));
#924=LINE('',#923,#922);
#925=CARTESIAN_POINT('',(19.1389,12.4949714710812,-12.7));
#926=VERTEX_POINT('',#925);
#927=EDGE_CURVE('E408',#895,#926,#924,.T.);
#928=ORIENTED_EDGE('',*,*,#927,.T.);
#929=DIRECTION('',(0.,0.,-1.));
#930=VECTOR('',#929,1.);
#931=CARTESIAN_POINT('',(19.1389,12.4949714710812,12.7));
#932=LINE('',#931,#930);
#933=CARTESIAN_POINT('',(19.1389,12.4949714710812,12.7));
#934=VERTEX_POINT('',#933);
#935=EDGE_CURVE('E464',#934,#926,#932,.T.);
#936=ORIENTED_EDGE('',*,*,#935,.F.);
#937=DIRECTION('',(0.,-1.,0.));
#938=VECTOR('',#937,1.);
#939=CARTESIAN_POINT('',(19.1389,12.4949714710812,12.7));
#940=LINE('',#939,#938);
#941=EDGE_CURVE('E674',#903,#934,#940,.T.);
#942=ORIENTED_EDGE('',*,*,#941,.F.);
#943=ORIENTED_EDGE('',*,*,#904,.T.);
#944=EDGE_LOOP('',(#928,#936,#942,#943));
#945=FACE_BOUND('',#944,.T.);
#946=ADVANCED_FACE('F912',(#945),#920,.F.);
#947=CARTESIAN_POINT('',(22.1361,9.144,12.7));
#948=DIRECTION('',(0.,0.,-1.));
#949=DIRECTION('',(-1.,0.,0.));
#950=AXIS2_PLACEMENT_3D('',#947,#948,#949);
#951=CYLINDRICAL_SURFACE('',#950,4.49580000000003);
#952=CARTESIAN_POINT('',(22.1361,9.144,-12.7));
#953=DIRECTION('',(0.,0.,1.));
#954=DIRECTION('',(1.,0.,0.));
#955=AXIS2_PLACEMENT_3D('',#952,#953,#954);
#956=CIRCLE('',#955,4.49580000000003);
#957=CARTESIAN_POINT('',(19.1389,5.79302852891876,-12.7));
#958=VERTEX_POINT('',#957);
#959=EDGE_CURVE('E412',#926,#958,#956,.T.);
#960=ORIENTED_EDGE('',*,*,#959,.T.);
#961=DIRECTION('',(0.,0.,-1.));
#962=VECTOR('',#961,1.);
#963=CARTESIAN_POINT('',(19.1389,5.79302852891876,12.7));
#964=LINE('',#963,#962);
#965=CARTESIAN_POINT('',(19.1389,5.79302852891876,12.7));
#966=VERTEX_POINT('',#965);
#967=EDGE_CURVE('E457',#966,#958,#964,.T.);
#968=ORIENTED_EDGE('',*,*,#967,.F.);
#969=CARTESIAN_POINT('',(22.1361,9.144,12.7));
#970=DIRECTION('',(0.,0.,1.));
#971=DIRECTION('',(1.,0.,0.));
#972=AXIS2_PLACEMENT_3D('',#969,#970,#971);
#973=CIRCLE('',#972,4.49580000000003);
#974=EDGE_CURVE('E671',#934,#966,#973,.T.);
#975=ORIENTED_EDGE('',*,*,#974,.F.);
#976=ORIENTED_EDGE('',*,*,#935,.T.);
#977=EDGE_LOOP('',(#960,#968,#975,#976));
#978=FACE_BOUND('',#977,.T.);
#979=ADVANCED_FACE('F919',(#978),#951,.T.);
#980=CARTESIAN_POINT('',(19.1389,-5.79302852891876,12.7));
#981=DIRECTION('',(1.,0.,0.));
#982=DIRECTION('',(0.,0.,-1.));
#983=AXIS2_PLACEMENT_3D('',#980,#981,#982);
#984=PLANE('',#983);
#985=DIRECTION('',(0.,-1.,0.));
#986=VECTOR('',#985,1.);
#987=CARTESIAN_POINT('',(19.1389,-5.79302852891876,-12.7));
#988=LINE('',#987,#986);
#989=CARTESIAN_POINT('',(19.1389,-5.79302852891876,-12.7));
#990=VERTEX_POINT('',#989);
#991=EDGE_CURVE('E417',#958,#990,#988,.T.);
#992=ORIENTED_EDGE('',*,*,#991,.T.);
#993=DIRECTION('',(0.,0.,-1.));
#994=VECTOR('',#993,1.);
#995=CARTESIAN_POINT('',(19.1389,-5.79302852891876,12.7));
#996=LINE('',#995,#994);
#997=CARTESIAN_POINT('',(19.1389,-5.79302852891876,12.7));
#998=VERTEX_POINT('',#997);
#999=EDGE_CURVE('E451',#998,#990,#996,.T.);
#1000=ORIENTED_EDGE('',*,*,#999,.F.);
#1001=DIRECTION('',(0.,-1.,0.));
#1002=VECTOR('',#1001,1.);
#1003=CARTESIAN_POINT('',(19.1389,-5.79302852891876,12.7));
#1004=LINE('',#1003,#1002);
#1005=EDGE_CURVE('E680',#966,#998,#1004,.T.);
#1006=ORIENTED_EDGE('',*,*,#1005,.F.);
#1007=ORIENTED_EDGE('',*,*,#967,.T.);
#1008=EDGE_LOOP('',(#992,#1000,#1006,#1007));
#1009=FACE_BOUND('',#1008,.T.);
#1010=ADVANCED_FACE('F922',(#1009),#984,.F.);
#1011=CARTESIAN_POINT('',(22.1361,-9.144,12.7));
#1012=DIRECTION('',(0.,0.,-1.));
#1013=DIRECTION('',(-1.,0.,0.));
#1014=AXIS2_PLACEMENT_3D('',#1011,#1012,#1013);
#1015=CYLINDRICAL_SURFACE('',#1014,4.49580000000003);
#1016=CARTESIAN_POINT('',(22.1361,-9.144,-12.7));
#1017=DIRECTION('',(0.,0.,1.));
#1018=DIRECTION('',(-1.,0.,0.));
#1019=AXIS2_PLACEMENT_3D('',#1016,#1017,#1018);
#1020=CIRCLE('',#1019,4.49580000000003);
#1021=CARTESIAN_POINT('',(19.1389,-12.4949714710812,-12.7));
#1022=VERTEX_POINT('',#1021);
#1023=EDGE_CURVE('E416',#990,#1022,#1020,.T.);
#1024=ORIENTED_EDGE('',*,*,#1023,.T.);
#1025=DIRECTION('',(0.,0.,-1.));
#1026=VECTOR('',#1025,1.);
#1027=CARTESIAN_POINT('',(19.1389,-12.4949714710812,12.7));
#1028=LINE('',#1027,#1026);
#1029=CARTESIAN_POINT('',(19.1389,-12.4949714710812,12.7));
#1030=VERTEX_POINT('',#1029);
#1031=EDGE_CURVE('E448',#1030,#1022,#1028,.T.);
#1032=ORIENTED_EDGE('',*,*,#1031,.F.);
#1033=CARTESIAN_POINT('',(22.1361,-9.144,12.7));
#1034=DIRECTION('',(0.,0.,1.));
#1035=DIRECTION('',(-1.,0.,0.));
#1036=AXIS2_PLACEMENT_3D('',#1033,#1034,#1035);
#1037=CIRCLE('',#1036,4.49580000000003);
#1038=EDGE_CURVE('E683',#998,#1030,#1037,.T.);
#1039=ORIENTED_EDGE('',*,*,#1038,.F.);
#1040=ORIENTED_EDGE('',*,*,#999,.T.);
#1041=EDGE_LOOP('',(#1024,#1032,#1039,#1040));
#1042=FACE_BOUND('',#1041,.T.);
#1043=ADVANCED_FACE('F923',(#1042),#1015,.T.);
#1044=CARTESIAN_POINT('',(19.1389,-17.1704,12.7));
#1045=DIRECTION('',(1.,0.,0.));
#1046=DIRECTION('',(0.,0.,-1.));
#1047=AXIS2_PLACEMENT_3D('',#1044,#1045,#1046);
#1048=PLANE('',#1047);
#1049=DIRECTION('',(0.,-1.,0.));
#1050=VECTOR('',#1049,1.);
#1051=CARTESIAN_POINT('',(19.1389,-17.1704,-12.7));
#1052=LINE('',#1051,#1050);
#1053=CARTESIAN_POINT('',(19.1389,-17.1704,-12.7));
#1054=VERTEX_POINT('',#1053);
#1055=EDGE_CURVE('E422',#1022,#1054,#1052,.T.);
#1056=ORIENTED_EDGE('',*,*,#1055,.T.);
#1057=DIRECTION('',(0.,0.,-1.));
#1058=VECTOR('',#1057,1.);
#1059=CARTESIAN_POINT('',(19.1389,-17.1704,12.7));
#1060=LINE('',#1059,#1058);
#1061=CARTESIAN_POINT('',(19.1389,-17.1704,12.7));
#1062=VERTEX_POINT('',#1061);
#1063=EDGE_CURVE('E447',#1062,#1054,#1060,.T.);
#1064=ORIENTED_EDGE('',*,*,#1063,.F.);
#1065=DIRECTION('',(0.,-1.,0.));
#1066=VECTOR('',#1065,1.);
#1067=CARTESIAN_POINT('',(19.1389,-17.1704,12.7));
#1068=LINE('',#1067,#1066);
#1069=EDGE_CURVE('E685',#1030,#1062,#1068,.T.);
#1070=ORIENTED_EDGE('',*,*,#1069,.F.);
#1071=ORIENTED_EDGE('',*,*,#1031,.T.);
#1072=EDGE_LOOP('',(#1056,#1064,#1070,#1071));
#1073=FACE_BOUND('',#1072,.T.);
#1074=ADVANCED_FACE('F926',(#1073),#1048,.F.);
#1075=CARTESIAN_POINT('',(-19.1389,-17.1704,12.7));
#1076=DIRECTION('',(0.,-1.,0.));
#1077=DIRECTION('',(0.,0.,-1.));
#1078=AXIS2_PLACEMENT_3D('',#1075,#1076,#1077);
#1079=PLANE('',#1078);
#1080=DIRECTION('',(-1.,0.,0.));
#1081=VECTOR('',#1080,1.);
#1082=CARTESIAN_POINT('',(-19.1389,-17.1704,-12.7));
#1083=LINE('',#1082,#1081);
#1084=CARTESIAN_POINT('',(-19.1389,-17.1704,-12.7));
#1085=VERTEX_POINT('',#1084);
#1086=EDGE_CURVE('E424',#1054,#1085,#1083,.T.);
#1087=ORIENTED_EDGE('',*,*,#1086,.T.);
#1088=DIRECTION('',(0.,0.,-1.));
#1089=VECTOR('',#1088,1.);
#1090=CARTESIAN_POINT('',(-19.1389,-17.1704,12.7));
#1091=LINE('',#1090,#1089);
#1092=CARTESIAN_POINT('',(-19.1389,-17.1704,12.7));
#1093=VERTEX_POINT('',#1092);
#1094=EDGE_CURVE('E445',#1093,#1085,#1091,.T.);
#1095=ORIENTED_EDGE('',*,*,#1094,.F.);
#1096=DIRECTION('',(-1.,0.,0.));
#1097=VECTOR('',#1096,1.);
#1098=CARTESIAN_POINT('',(-19.1389,-17.1704,12.7));
#1099=LINE('',#1098,#1097);
#1100=EDGE_CURVE('E690',#1062,#1093,#1099,.T.);
#1101=ORIENTED_EDGE('',*,*,#1100,.F.);
#1102=ORIENTED_EDGE('',*,*,#1063,.T.);
#1103=EDGE_LOOP('',(#1087,#1095,#1101,#1102));
#1104=FACE_BOUND('',#1103,.T.);
#1105=ADVANCED_FACE('F788',(#1104),#1079,.F.);
#1106=CARTESIAN_POINT('',(-19.1389,-12.4949714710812,12.7));
#1107=DIRECTION('',(-1.,0.,0.));
#1108=DIRECTION('',(0.,0.,1.));
#1109=AXIS2_PLACEMENT_3D('',#1106,#1107,#1108);
#1110=PLANE('',#1109);
#1111=DIRECTION('',(0.,1.,0.));
#1112=VECTOR('',#1111,1.);
#1113=CARTESIAN_POINT('',(-19.1389,-12.4949714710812,-12.7));
#1114=LINE('',#1113,#1112);
#1115=CARTESIAN_POINT('',(-19.1389,-12.4949714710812,-12.7));
#1116=VERTEX_POINT('',#1115);
#1117=EDGE_CURVE('E426',#1085,#1116,#1114,.T.);
#1118=ORIENTED_EDGE('',*,*,#1117,.T.);
#1119=DIRECTION('',(0.,0.,-1.));
#1120=VECTOR('',#1119,1.);
#1121=CARTESIAN_POINT('',(-19.1389,-12.4949714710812,12.7));
#1122=LINE('',#1121,#1120);
#1123=CARTESIAN_POINT('',(-19.1389,-12.4949714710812,12.7));
#1124=VERTEX_POINT('',#1123);
#1125=EDGE_CURVE('E311',#1124,#1116,#1122,.T.);
#1126=ORIENTED_EDGE('',*,*,#1125,.F.);
#1127=DIRECTION('',(0.,1.,0.));
#1128=VECTOR('',#1127,1.);
#1129=CARTESIAN_POINT('',(-19.1389,-12.4949714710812,12.7));
#1130=LINE('',#1129,#1128);
#1131=EDGE_CURVE('E297',#1093,#1124,#1130,.T.);
#1132=ORIENTED_EDGE('',*,*,#1131,.F.);
#1133=ORIENTED_EDGE('',*,*,#1094,.T.);
#1134=EDGE_LOOP('',(#1118,#1126,#1132,#1133));
#1135=FACE_BOUND('',#1134,.T.);
#1136=ADVANCED_FACE('F794',(#1135),#1110,.F.);
#1137=CARTESIAN_POINT('',(-22.1361,-9.144,12.7));
#1138=DIRECTION('',(0.,0.,-1.));
#1139=DIRECTION('',(-1.,0.,0.));
#1140=AXIS2_PLACEMENT_3D('',#1137,#1138,#1139);
#1141=CYLINDRICAL_SURFACE('',#1140,4.49580000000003);
#1142=CARTESIAN_POINT('',(-22.1361,-9.144,-12.7));
#1143=DIRECTION('',(0.,0.,1.));
#1144=DIRECTION('',(-1.,0.,0.));
#1145=AXIS2_PLACEMENT_3D('',#1142,#1143,#1144);
#1146=CIRCLE('',#1145,4.49580000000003);
#1147=CARTESIAN_POINT('',(-19.1389,-5.79302852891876,-12.7));
#1148=VERTEX_POINT('',#1147);
#1149=EDGE_CURVE('E307',#1116,#1148,#1146,.T.);
#1150=ORIENTED_EDGE('',*,*,#1149,.T.);
#1151=DIRECTION('',(0.,0.,-1.));
#1152=VECTOR('',#1151,1.);
#1153=CARTESIAN_POINT('',(-19.1389,-5.79302852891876,12.7));
#1154=LINE('',#1153,#1152);
#1155=CARTESIAN_POINT('',(-19.1389,-5.79302852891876,12.7));
#1156=VERTEX_POINT('',#1155);
#1157=EDGE_CURVE('E306',#1156,#1148,#1154,.T.);
#1158=ORIENTED_EDGE('',*,*,#1157,.F.);
#1159=CARTESIAN_POINT('',(-22.1361,-9.144,12.7));
#1160=DIRECTION('',(0.,0.,1.));
#1161=DIRECTION('',(-1.,0.,0.));
#1162=AXIS2_PLACEMENT_3D('',#1159,#1160,#1161);
#1163=CIRCLE('',#1162,4.49580000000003);
#1164=EDGE_CURVE('E295',#1124,#1156,#1163,.T.);
#1165=ORIENTED_EDGE('',*,*,#1164,.F.);
#1166=ORIENTED_EDGE('',*,*,#1125,.T.);
#1167=EDGE_LOOP('',(#1150,#1158,#1165,#1166));
#1168=FACE_BOUND('',#1167,.T.);
#1169=ADVANCED_FACE('F310',(#1168),#1141,.T.);
#1170=CARTESIAN_POINT('',(-19.1389,5.79302852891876,12.7));
#1171=DIRECTION('',(-1.,0.,0.));
#1172=DIRECTION('',(0.,0.,1.));
#1173=AXIS2_PLACEMENT_3D('',#1170,#1171,#1172);
#1174=PLANE('',#1173);
#1175=DIRECTION('',(0.,1.,0.));
#1176=VECTOR('',#1175,1.);
#1177=CARTESIAN_POINT('',(-19.1389,5.79302852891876,-12.7));
#1178=LINE('',#1177,#1176);
#1179=CARTESIAN_POINT('',(-19.1389,5.79302852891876,-12.7));
#1180=VERTEX_POINT('',#1179);
#1181=EDGE_CURVE('E180',#1148,#1180,#1178,.T.);
#1182=ORIENTED_EDGE('',*,*,#1181,.T.);
#1183=DIRECTION('',(0.,0.,-1.));
#1184=VECTOR('',#1183,1.);
#1185=CARTESIAN_POINT('',(-19.1389,5.79302852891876,12.7));
#1186=LINE('',#1185,#1184);
#1187=CARTESIAN_POINT('',(-19.1389,5.79302852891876,12.7));
#1188=VERTEX_POINT('',#1187);
#1189=EDGE_CURVE('E315',#1188,#1180,#1186,.T.);
#1190=ORIENTED_EDGE('',*,*,#1189,.F.);
#1191=DIRECTION('',(0.,1.,0.));
#1192=VECTOR('',#1191,1.);
#1193=CARTESIAN_POINT('',(-19.1389,5.79302852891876,12.7));
#1194=LINE('',#1193,#1192);
#1195=EDGE_CURVE('E296',#1156,#1188,#1194,.T.);
#1196=ORIENTED_EDGE('',*,*,#1195,.F.);
#1197=ORIENTED_EDGE('',*,*,#1157,.T.);
#1198=EDGE_LOOP('',(#1182,#1190,#1196,#1197));
#1199=FACE_BOUND('',#1198,.T.);
#1200=ADVANCED_FACE('F313',(#1199),#1174,.F.);
#1201=CARTESIAN_POINT('',(-22.1361,9.144,12.7));
#1202=DIRECTION('',(0.,0.,-1.));
#1203=DIRECTION('',(-1.,0.,0.));
#1204=AXIS2_PLACEMENT_3D('',#1201,#1202,#1203);
#1205=CYLINDRICAL_SURFACE('',#1204,4.49580000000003);
#1206=CARTESIAN_POINT('',(-22.1361,9.144,-12.7));
#1207=DIRECTION('',(0.,0.,1.));
#1208=DIRECTION('',(1.,0.,0.));
#1209=AXIS2_PLACEMENT_3D('',#1206,#1207,#1208);
#1210=CIRCLE('',#1209,4.49580000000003);
#1211=EDGE_CURVE('E182',#1180,#29,#1210,.T.);
#1212=ORIENTED_EDGE('',*,*,#1211,.T.);
#1213=ORIENTED_EDGE('',*,*,#54,.F.);
#1214=CARTESIAN_POINT('',(-22.1361,9.144,12.7));
#1215=DIRECTION('',(0.,0.,1.));
#1216=DIRECTION('',(1.,0.,0.));
#1217=AXIS2_PLACEMENT_3D('',#1214,#1215,#1216);
#1218=CIRCLE('',#1217,4.49580000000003);
#1219=EDGE_CURVE('E59',#1188,#47,#1218,.T.);
#1220=ORIENTED_EDGE('',*,*,#1219,.F.);
#1221=ORIENTED_EDGE('',*,*,#1189,.T.);
#1222=EDGE_LOOP('',(#1212,#1213,#1220,#1221));
#1223=FACE_BOUND('',#1222,.T.);
#1224=ADVANCED_FACE('F799',(#1223),#1205,.T.);
#1225=CARTESIAN_POINT('',(-22.1361,9.144,12.7));
#1226=DIRECTION('',(0.,0.,1.));
#1227=DIRECTION('',(1.,0.,0.));
#1228=AXIS2_PLACEMENT_3D('',#1225,#1226,#1227);
#1229=PLANE('',#1228);
#1230=ORIENTED_EDGE('',*,*,#48,.T.);
#1231=ORIENTED_EDGE('',*,*,#84,.T.);
#1232=ORIENTED_EDGE('',*,*,#115,.T.);
#1233=ORIENTED_EDGE('',*,*,#146,.T.);
#1234=ORIENTED_EDGE('',*,*,#177,.T.);
#1235=ORIENTED_EDGE('',*,*,#210,.T.);
#1236=ORIENTED_EDGE('',*,*,#241,.T.);
#1237=ORIENTED_EDGE('',*,*,#274,.T.);
#1238=ORIENTED_EDGE('',*,*,#305,.T.);
#1239=ORIENTED_EDGE('',*,*,#338,.T.);
#1240=ORIENTED_EDGE('',*,*,#369,.T.);
#1241=ORIENTED_EDGE('',*,*,#402,.T.);
#1242=ORIENTED_EDGE('',*,*,#433,.T.);
#1243=ORIENTED_EDGE('',*,*,#466,.T.);
#1244=ORIENTED_EDGE('',*,*,#497,.T.);
#1245=ORIENTED_EDGE('',*,*,#530,.T.);
#1246=ORIENTED_EDGE('',*,*,#561,.T.);
#1247=ORIENTED_EDGE('',*,*,#594,.T.);
#1248=ORIENTED_EDGE('',*,*,#625,.T.);
#1249=ORIENTED_EDGE('',*,*,#658,.T.);
#1250=ORIENTED_EDGE('',*,*,#689,.T.);
#1251=ORIENTED_EDGE('',*,*,#722,.T.);
#1252=ORIENTED_EDGE('',*,*,#753,.T.);
#1253=ORIENTED_EDGE('',*,*,#786,.T.);
#1254=ORIENTED_EDGE('',*,*,#817,.T.);
#1255=ORIENTED_EDGE('',*,*,#848,.T.);
#1256=ORIENTED_EDGE('',*,*,#879,.T.);
#1257=ORIENTED_EDGE('',*,*,#910,.T.);
#1258=ORIENTED_EDGE('',*,*,#941,.T.);
#1259=ORIENTED_EDGE('',*,*,#974,.T.);
#1260=ORIENTED_EDGE('',*,*,#1005,.T.);
#1261=ORIENTED_EDGE('',*,*,#1038,.T.);
#1262=ORIENTED_EDGE('',*,*,#1069,.T.);
#1263=ORIENTED_EDGE('',*,*,#1100,.T.);
#1264=ORIENTED_EDGE('',*,*,#1131,.T.);
#1265=ORIENTED_EDGE('',*,*,#1164,.T.);
#1266=ORIENTED_EDGE('',*,*,#1195,.T.);
#1267=ORIENTED_EDGE('',*,*,#1219,.T.);
#1268=EDGE_LOOP('',(#1230,#1231,#1232,#1233,#1234,#1235,#1236,#1237,#1238,#1239,#1240,#1241,
#1242,#1243,#1244,#1245,#1246,#1247,#1248,#1249,#1250,#1251,#1252,#1253,#1254,#1255,#1256,#1257,
#1258,#1259,#1260,#1261,#1262,#1263,#1264,#1265,#1266,#1267));
#1269=FACE_BOUND('',#1268,.T.);
#1270=ADVANCED_FACE('F298',(#1269),#1229,.T.);
#1271=CARTESIAN_POINT('',(-22.1361,9.144,-12.7));
#1272=DIRECTION('',(0.,0.,1.));
#1273=DIRECTION('',(1.,0.,0.));
#1274=AXIS2_PLACEMENT_3D('',#1271,#1272,#1273);
#1275=PLANE('',#1274);
#1276=ORIENTED_EDGE('',*,*,#32,.F.);
#1277=ORIENTED_EDGE('',*,*,#1211,.F.);
#1278=ORIENTED_EDGE('',*,*,#1181,.F.);
#1279=ORIENTED_EDGE('',*,*,#1149,.F.);
#1280=ORIENTED_EDGE('',*,*,#1117,.F.);
#1281=ORIENTED_EDGE('',*,*,#1086,.F.);
#1282=ORIENTED_EDGE('',*,*,#1055,.F.);
#1283=ORIENTED_EDGE('',*,*,#1023,.F.);
#1284=ORIENTED_EDGE('',*,*,#991,.F.);
#1285=ORIENTED_EDGE('',*,*,#959,.F.);
#1286=ORIENTED_EDGE('',*,*,#927,.F.);
#1287=ORIENTED_EDGE('',*,*,#896,.F.);
#1288=ORIENTED_EDGE('',*,*,#865,.F.);
#1289=ORIENTED_EDGE('',*,*,#834,.F.);
#1290=ORIENTED_EDGE('',*,*,#803,.F.);
#1291=ORIENTED_EDGE('',*,*,#771,.F.);
#1292=ORIENTED_EDGE('',*,*,#739,.F.);
#1293=ORIENTED_EDGE('',*,*,#707,.F.);
#1294=ORIENTED_EDGE('',*,*,#675,.F.);
#1295=ORIENTED_EDGE('',*,*,#643,.F.);
#1296=ORIENTED_EDGE('',*,*,#611,.F.);
#1297=ORIENTED_EDGE('',*,*,#579,.F.);
#1298=ORIENTED_EDGE('',*,*,#547,.F.);
#1299=ORIENTED_EDGE('',*,*,#515,.F.);
#1300=ORIENTED_EDGE('',*,*,#483,.F.);
#1301=ORIENTED_EDGE('',*,*,#451,.F.);
#1302=ORIENTED_EDGE('',*,*,#419,.F.);
#1303=ORIENTED_EDGE('',*,*,#387,.F.);
#1304=ORIENTED_EDGE('',*,*,#355,.F.);
#1305=ORIENTED_EDGE('',*,*,#323,.F.);
#1306=ORIENTED_EDGE('',*,*,#291,.F.);
#1307=ORIENTED_EDGE('',*,*,#259,.F.);
#1308=ORIENTED_EDGE('',*,*,#227,.F.);
#1309=ORIENTED_EDGE('',*,*,#195,.F.);
#1310=ORIENTED_EDGE('',*,*,#163,.F.);
#1311=ORIENTED_EDGE('',*,*,#132,.F.);
#1312=ORIENTED_EDGE('',*,*,#101,.F.);
#1313=ORIENTED_EDGE('',*,*,#70,.F.);
#1314=EDGE_LOOP('',(#1276,#1277,#1278,#1279,#1280,#1281,#1282,#1283,#1284,#1285,#1286,#1287,
#1288,#1289,#1290,#1291,#1292,#1293,#1294,#1295,#1296,#1297,#1298,#1299,#1300,#1301,#1302,#1303,
#1304,#1305,#1306,#1307,#1308,#1309,#1310,#1311,#1312,#1313));
#1315=FACE_BOUND('',#1314,.T.);
#1316=ADVANCED_FACE('F585',(#1315),#1275,.F.);
#1317=CLOSED_SHELL('',(#58,#89,#120,#151,#182,#215,#246,#279,#310,#343,#374,#407,#438,#471,#502,
#535,#566,#599,#630,#663,#694,#727,#758,#791,#822,#853,#884,#915,#946,#979,#1010,#1043,#1074,
#1105,#1136,#1169,#1200,#1224,#1270,#1316));
#1318=MANIFOLD_SOLID_BREP('B2',#1317);
#1319=ADVANCED_BREP_SHAPE_REPRESENTATION('',(#18,#1318),#14);
#1320=SHAPE_DEFINITION_REPRESENTATION(#9,#1319);
ENDSEC;
END-ISO-10303-21;
